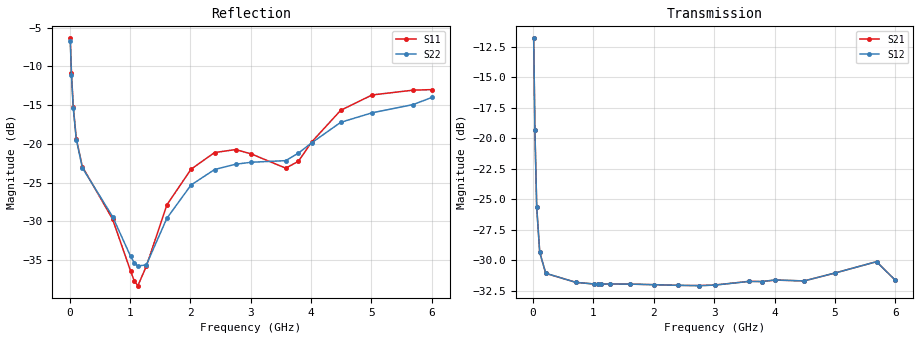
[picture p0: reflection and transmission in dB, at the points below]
! Integrated Device Technology
! Corporate Headquarters
! 6024 Silver Creek Valley Road
! San Jose, CA 95138  USA
! Phone:  1-408-284-8200
! Toll Free:  1-800-223-1366
! Webpage:  http://www.idt.com/
! Timing and RF Division
! 515 Groton Road, Suite 102
! Westford, MA 01886-6024
! Device:  F1951
! Description: 6-bit 0.5 dB Digital Step Attenuator
! Frequency:  100.0 -  4000.00 MHz
! Package:  4x4 mm Thin QFN Plastic Package: 24 pin
! Ports:  2 RF, 6 DC
!  Pin  1  = NC
!  Pin  2  = RF1  =  Port 1
!  Pin  3  = GND
!  Pin  4  = NC
!  Pin  5  = Serial Data Out (SDO)
!  Pin  6  = NC
!  Pin  7  = Reset Bar ( RSTb)
!  Pin  8  = Clock (CLK)
!  Pin  9  = Chip Select Bar (CSb)
!  Pin 10  = NC
!  Pin 11  = Serial Data In (SDI)
!  Pin 12  = NC
!  Pin 13  = NC
!  Pin 14  = VDD
!  Pin 15  = NC
!  Pin 16  = GND
!  Pin 17  = RF2  =  Port 2
!  Pin 18  = NC
!  Pin 19  = GND
!  Pin 20  = GND
!  Pin 21  = GND
!  Pin 22  = GND
!  Pin 23  = GND
!  Pin 24  = GND
! State:  62
! Atten State:  31.0 dB
! Voltage:  +3.30 Volts
! Current:  0.481 mA
! Data:  The device was measured on a F195X evaluation board which has
!  individual transmission lines to the RF pins.  Data was collected
!  de-embedded using a Automatic Fixture Removal [AFR] (Keysight Technologies).
!  The reference plane is the edge of the package pin.
! Misc:  Lot Code  1225BCA
!  Action Tracker AT0399
! Date Measured:  2018-09-13
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# GHz S dB R 50
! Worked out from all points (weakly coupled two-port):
!   600 points, 10 MHz to 6 GHz, reference 50 ohm
!   highest |S21| = -11.80 dB at 10 MHz (marker M1); lowest = -32.1 dB at 2.75 GHz (marker M2)
!   lowest |S11| = -38.3 dB at 1.13 GHz (marker M3), VSWR 1.02, Z = 48.8 + j0.222 ohm
!   |S11| at or under -10 dB: 25.5 MHz to end of sweep
!   |S22| runs from -36.2 to -6.7 dB; largest |S21 - S12| = 0.00018
!   S11 on the Smith chart (normalised r, x): 10 MHz: 1.77, -1.23; 30 MHz: 1.11, -0.62; 60 MHz: 0.98, -0.35; 1.07 GHz: 0.97, -0.00; 6 GHz: 0.81, +0.37
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0.01  -6.39 -34.1  -11.80 -43.4  -11.80 -43.4  -6.68 -34.6
0.03  -10.92 -63.2  -19.29 -67.8  -19.29 -67.9  -11.15 -62.8
0.06  -15.24 -83.2  -25.64 -62.0  -25.64 -62.0  -15.43 -82.9
0.11  -19.33 -101.1  -29.35 -44.3  -29.35 -44.2  -19.44 -101.0
0.21  -22.93 -119.5  -31.07 -27.1  -31.06 -27.1  -23.08 -119.6
0.71  -29.69 -136.5  -31.81 -14.0  -31.81 -14.0  -29.37 -138.9
1.01  -36.42 -158.2  -31.94 -14.2  -31.94 -14.2  -34.52 -153.9
1.07  -37.67 -172.6  -31.96 -14.3  -31.96 -14.2  -35.34 -160.4
1.13  -38.29 169.3  -31.95 -14.3  -31.95 -14.3  -35.75 -171.1
1.27  -35.78 132.0  -31.94 -14.9  -31.94 -14.8  -35.61 162.8
1.61  -27.88 115.3  -31.95 -16.8  -31.95 -16.8  -29.60 134.1
2.01  -23.27 122.9  -32.00 -19.6  -32.00 -19.6  -25.31 134.8
2.4  -21.12 133.2  -32.05 -22.1  -32.05 -22.1  -23.31 140.2
2.75  -20.73 141.6  -32.07 -24.4  -32.08 -24.4  -22.62 144.4
3.01  -21.30 145.6  -32.03 -25.9  -32.03 -25.8  -22.37 145.1
3.58  -23.13 124.4  -31.72 -29.5  -31.73 -29.5  -22.16 128.2
3.79  -22.24 108.7  -31.74 -31.0  -31.74 -30.9  -21.19 121.4
4.01  -19.75 100.4  -31.62 -32.5  -31.61 -32.5  -19.86 116.1
4.49  -15.67 98.8  -31.69 -35.1  -31.69 -35.0  -17.22 114.3
5.01  -13.69 107.5  -31.03 -35.7  -31.03 -35.6  -15.99 116.5
5.69  -13.07 112.3  -30.11 -47.7  -30.11 -47.7  -14.93 109.0
6  -13.00 105.9  -31.63 -46.5  -31.63 -46.5  -14.01 105.1
